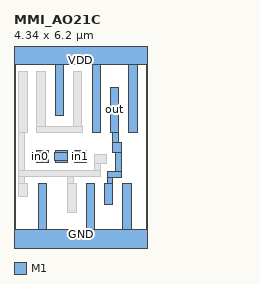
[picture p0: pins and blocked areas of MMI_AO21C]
MACRO MMI_AO21C
	CLASS CORE ;
	FOREIGN MMI_AO21C 0 0 ;
	SIZE 4.34 BY 6.2 ;
	SYMMETRY X Y ;
	SITE CORE1 ;
	PIN out
		DIRECTION output ;
		USE SIGNAL ;
		PORT
			LAYER M1 ;
			RECT 3.145 3.58 3.425 5.05 ;
			LAYER M1 ;
			RECT 3.23 3.24 3.425 3.58 ;
			LAYER M1 ;
			RECT 3.23 2.915 3.515 3.24 ;
			LAYER M1 ;
			RECT 3.325 2.315 3.515 2.915 ;
			LAYER M1 ;
			RECT 3.035 2.12 3.515 2.315 ;
			LAYER M1 ;
			RECT 3.035 1.915 3.225 2.12 ;
			LAYER M1 ;
			RECT 2.95 1.215 3.23 1.915 ;
		END
		AntennaDiffArea 1.0164 ;
	END out
	PIN in1
		DIRECTION input ;
		USE SIGNAL ;
		PORT
			LAYER M1 ;
			RECT 1.98 2.93 2.36 2.98 ;
			LAYER M1 ;
			RECT 1.95 2.65 2.36 2.93 ;
			LAYER M1 ;
			RECT 1.98 2.6 2.36 2.65 ;
		END
		AntennaGateArea 0.468 ;
	END in1
	PIN GND
		DIRECTION inout ;
		USE GROUND ;
		PORT
			LAYER M1 ;
			RECT 0.795 0.42 1.075 1.92 ;
			LAYER M1 ;
			RECT 2.36 0.42 2.64 1.915 ;
			LAYER M1 ;
			RECT 3.54 0.42 3.82 1.915 ;
			LAYER M1 ;
			RECT 0 -0.42 4.34 0.42 ;
		END
	END GND
	PIN in2
		DIRECTION input ;
		USE SIGNAL ;
		PORT
			LAYER M1 ;
			RECT 1.36 2.93 1.74 2.98 ;
			LAYER M1 ;
			RECT 1.33 2.65 1.74 2.93 ;
			LAYER M1 ;
			RECT 1.36 2.6 1.74 2.65 ;
		END
		AntennaGateArea 0.468 ;
	END in2
	PIN VDD
		DIRECTION inout ;
		USE POWER ;
		PORT
			LAYER M1 ;
			RECT 0 5.78 4.34 6.62 ;
			LAYER M1 ;
			RECT 1.34 4.13 1.62 5.78 ;
			LAYER M1 ;
			RECT 2.555 3.58 2.835 5.78 ;
			LAYER M1 ;
			RECT 3.735 3.58 4.015 5.78 ;
		END
	END VDD
	PIN in0
		DIRECTION input ;
		USE SIGNAL ;
		PORT
			LAYER M1 ;
			RECT 0.74 2.93 1.12 2.98 ;
			LAYER M1 ;
			RECT 0.555 2.65 1.12 2.93 ;
			LAYER M1 ;
			RECT 0.74 2.6 1.12 2.65 ;
		END
		AntennaGateArea 0.39 ;
	END in0
	OBS
		LAYER M1 ;
		RECT 0.16 3.57 0.44 5.58 ;
		LAYER M1 ;
		RECT 0.75 3.76 1.03 5.58 ;
		LAYER M1 ;
		RECT 1.93 3.76 2.21 5.58 ;
		LAYER M1 ;
		RECT 0.75 3.57 2.245 3.76 ;
		LAYER M1 ;
		RECT 0.16 2.32 0.355 3.57 ;
		LAYER M1 ;
		RECT 2.62 2.565 3.03 2.845 ;
		LAYER M1 ;
		RECT 2.62 2.32 2.81 2.565 ;
		LAYER M1 ;
		RECT 0.16 2.125 2.81 2.32 ;
		LAYER M1 ;
		RECT 0.16 1.92 0.355 2.125 ;
		LAYER M1 ;
		RECT 1.75 1.92 1.945 2.125 ;
		LAYER M1 ;
		RECT 0.16 1.47 0.44 1.92 ;
		LAYER M1 ;
		RECT 1.755 0.95 2.035 1.92 ;
	END
END MMI_AO21C
